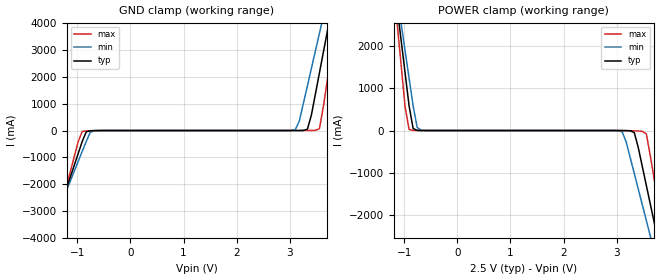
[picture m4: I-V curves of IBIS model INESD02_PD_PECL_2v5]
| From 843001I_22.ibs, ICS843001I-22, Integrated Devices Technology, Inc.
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[Model] INESD02_PD_PECL_2v5
Model_type   Input
Polarity   Non-Inverting
Vinl = 0.8V
Vinh = 2.0V
|   typ   min   max
C_comp   2pF   1.5pF   2.5pF
|   typ   min   max
[Voltage range]  2.5V   2.375V   2.625V
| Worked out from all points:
|   GND clamp passes 1 mA (typ) near -0.59 V on its own axis
|   POWER clamp passes 1 mA (typ) near -0.69 V on its own axis
[GND_clamp]
|Voltage   I(typ)   I(min)   I(max)
-2.5V     -9.799A    -8.591A    -11.84A
-1.591V   -4.431A    -4.121A    -4.98A
-1.439V   -3.536A    -3.377A    -3.837A
-909.1mV  -407.1mA   -774.3mA   -35.24mA
-833.3mV  -48.47mA   -403.4mA   -14.47mA
-681.8mV  -2.863mA   -7.067mA   -5.73mA
3.106V    167.2uA    32.81mA    49.66uA
3.333V    47.81mA    1.661A     649.6uA
3.561V    2.15A      3.618A     75.79mA
3.712V    3.718A     4.923A     1.92A
3.864V    5.287A     6.229A     3.927A
5V        17.07A     16.03A     18.99A
[POWER_clamp]
|Voltage   I(typ)   I(min)   I(max)
-2.5V     17.07A     14.96A     20.65A
-1.136V   2.934A     3.193A     2.572A
-1.061V   2.15A      2.541A     1.569A
-909.1mV  582.4mA    1.237A     24.21mA
-833.3mV  47.81mA    585.7mA    3.595mA
-681.8mV  586.4uA    6.896mA    416.8uA
3.106V    -1.127mA   -30.71mA   -286.5uA
3.333V    -48.47mA   -1.016A    -7.036mA
3.485V    -853.6mA   -1.759A    -17.14mA
3.712V    -2.194A    -2.874A    -1.179A
3.939V    -3.536A    -3.991A    -2.894A
5V        -9.799A    -9.206A    -10.89A
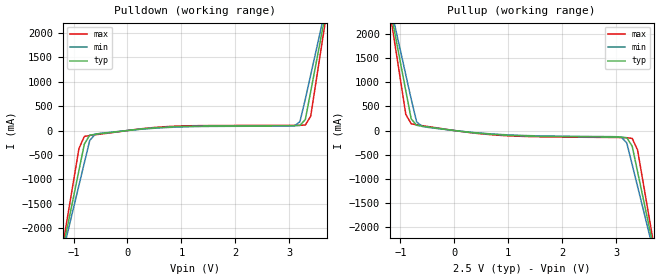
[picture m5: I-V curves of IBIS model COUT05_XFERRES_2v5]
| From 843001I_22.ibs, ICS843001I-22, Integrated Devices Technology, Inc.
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[Model] COUT05_XFERRES_2v5
Model_type   Output
Polarity   Non-Inverting
|   typ   min   max
C_comp   2pF   1.5pF   2.5pF
Vmeas = 1.25V
Rref = 50
Vref = 1.25V
|   typ   min   max
[Voltage range]   2.5V   2.375V   2.625V
[Pullup Reference]   2.5V   2.375V   2.625V
[Pulldown Reference]   0.0V   0.0V   0.0V
[GND Clamp Reference]   0.0V   0.0V   0.0V
[POWER Clamp Reference]   2.5V   2.375V   2.625V
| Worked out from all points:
|   slope of the pulldown table from 0 to 0.375 V, typ, clamps not added: 8.86 ohm
|   slope of the pullup table from 0 to 0.375 V, typ, clamps not added: 7.92 ohm
[pulldown]
|Voltage   I (typ)   I (min)   I (max)
-2.5V     -9.407A    -8.467A    -10.89A
-1.2V     -2.429A    -2.497A    -2.347A
-1.1V     -1.891A    -2.038A    -1.688A
-900mV    -815.3mA   -1.118A    -369.3mA
-800mV    -277.7mA   -658.8mA   -121mA
-600mV    -75.94mA   -74.93mA   -86.3mA
3.1V      97.86mA    96.58mA    105.9mA
3.3V      225.3mA    641.2mA    111.8mA
3.4V      794.9mA    1.136A     294.5mA
3.6V      1.955A     2.127A     1.718A
3.7V      2.536A     2.623A     2.431A
5V        10.13A     9.107A     11.75A
[pullup]
|Voltage   I (typ)   I (min)   I (max)
-2.5V     10.24A     9.216A     11.88A
-1.2V     2.591A     2.667A     2.502A
-1.1V     2.002A     2.164A     1.78A
-900mV    823.6mA    1.156A     334.8mA
-800mV    243.2mA    652.3mA    139.1mA
-600mV    90.17mA    86.22mA    102.1mA
3.1V      -138.3mA   -138.9mA   -146.3mA
3.3V      -324.7mA   -709.4mA   -163.3mA
3.4V      -856.2mA   -1.163A    -404.9mA
3.6V      -1.922A    -2.073A    -1.713A
3.7V      -2.455A    -2.529A    -2.368A
5V        -9.405A    -8.469A    -10.89A
[Ramp]
|   typ   min   max
dV/dt_r   1.50/0.6n   1.50/0.80n   1.50/0.4n
dV/dt_f   1.50/0.6n   1.50/0.80n   1.50/0.4n
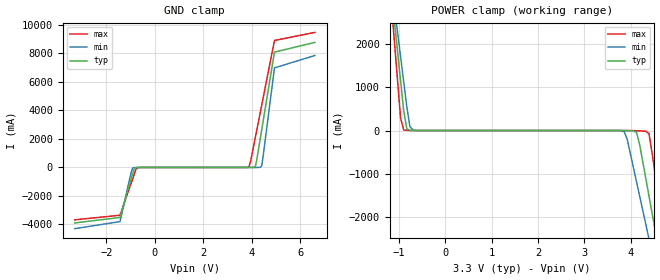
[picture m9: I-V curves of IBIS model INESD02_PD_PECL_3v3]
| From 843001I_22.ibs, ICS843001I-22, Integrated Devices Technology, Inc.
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[Model] INESD02_PD_PECL_3v3
Model_type  Input
Polarity   Non-Inverting
Vinl = 0.8V
Vinh = 2.0V
|   typ   min   max
C_comp   2pF   1.5pF   2.5pF
|   typ   min   max
[Voltage range]  3.3V   3.15V   3.45V
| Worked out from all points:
|   GND clamp passes 1 mA (typ) near -0.59 V on its own axis
|   POWER clamp passes 1 mA (typ) near -0.70 V on its own axis
[GND_clamp]
-3.3V     -3.894A    -4.294A    -3.674A
-1.434V   -3.506A    -3.799A    -3.352A
-974.8mV  -794.1mA   -331.5mA   -1.096A
-909.1mV  -407.1mA   -35.25mA   -774.3mA
-777.8mV  -10.55mA   -10.84mA   -133.1mA
-646.5mV  -1.912mA   -4.151mA   -2.665mA
3.884V    141.8uA    72.03uA    57.99mA
3.95V     342.2uA    75.94uA    423.8mA
4.146V    78.32mA    440.9uA    2.118A
4.409V    2.651A     112.4mA    4.38A
4.934V    8.093A     6.984A     8.908A
6.6V      8.773A     7.854A     9.475A
[POWER_clamp]
-3.3V     6.7A       6.327A     7.39A
-1.165V   3.23A      3.44A      2.951A
-1.031V   1.843A     2.286A     1.176A
-963.9mV  1.149A     1.709A     289.6mA
-896.9mV  456.5mA    1.133A     15.4mA
-695.9mV  792.2uA    10.73mA    555.6uA
3.861V    -556.7uA   -26.14mA   -39.45uA
4.129V    -41.85mA   -1.19A     -4.904mA
4.33V     -1.119A    -2.176A    -17.86mA
4.531V    -2.305A    -3.163A    -1.019A
4.732V    -3.492A    -4.151A    -2.536A
6.6V      -5.075A    -5.468A    -4.558A
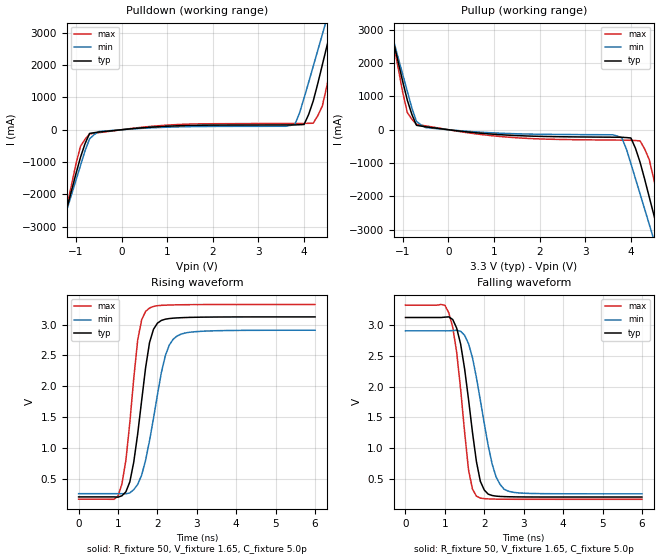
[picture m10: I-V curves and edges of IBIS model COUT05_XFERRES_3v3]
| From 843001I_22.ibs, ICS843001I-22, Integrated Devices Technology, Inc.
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[Model] COUT05_XFERRES_3v3
Model_type   Output
Polarity   Non-Inverting
|   typ   min   max
C_comp   2pF   1.5pF   2.5pF
Vmeas = 1.65V
Rref = 50
Vref = 1.65V
|   typ   min   max
[Voltage range]   3.3V   3.135V   3.465V
[Pullup Reference]   3.3V   3.135V   3.465V
[Pulldown Reference]   0.0V   0.0V   0.0V
[GND Clamp Reference]   0.0V   0.0V   0.0V
[POWER Clamp Reference]   3.3V   3.135V   3.465V
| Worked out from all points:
|   slope of the pulldown table from 0 to 0.495 V, typ, clamps not added: 7.71 ohm
|   slope of the pullup table from 0 to 0.495 V, typ, clamps not added: 6.44 ohm
|   rising waveform, R_fixture 50, V_fixture 1.65, C_fixture 5.0p: 20-80 % time 355ps typ, 463ps min, 291ps max; typ from 0.201 V to 3.12 V
|   falling waveform, R_fixture 50, V_fixture 1.65, C_fixture 5.0p: 20-80 % time 361ps typ, 456ps min, 309ps max; typ from 3.12 V to 0.201 V
[pulldown]
|Voltage   I (typ)   I (min)   I (max)
-3.3V     -13.74A    -12.12A    -16.25A
-1.4V     -3.526A    -3.407A    -3.72A
-1.3V     -2.987A    -2.948A    -3.058A
-900mV    -857.7mA   -1.112A    -513.9mA
-700mV    -114.2mA   -281.1mA   -130.4mA
3.8V      149.8mA    170.1mA    194.9mA
4V        161.9mA    982.2mA    196.3mA
4.2V      887.5mA    1.963A     202.2mA
4.4V      2.009A     2.952A     734.1mA
4.6V      3.172A     3.944A     2.074A
4.8V      4.339A     4.937A     3.509A
6.6V      15.05A     14.04A     16.69A
[pullup]
|Voltage   I (typ)   I (min)   I (max)
-3.3V     15.02A     13.23A     17.78A
-1.3V     3.212A     3.164A     3.296A
-900mV    885.7mA    1.151A     514.2mA
-700mV    133mA      248.7mA    161.5mA
3.6V      -223.7mA   -151.5mA   -310mA
3.8V      -226.2mA   -242.1mA   -312.1mA
4V        -247.6mA   -1.022A    -317.2mA
4.3V      -1.48A     -2.38A     -576.5mA
4.5V      -2.547A    -3.289A    -1.474A
4.6V      -3.081A    -3.743A    -2.13A
4.8V      -4.149A    -4.654A    -3.444A
6.6V      -13.78A    -12.87A    -15.26A
[Ramp]
|   typ   min   max
dV/dt_r   1.98/0.6n   1.98/0.80n   1.98/0.4n
dV/dt_f   1.98/0.6n   1.98/0.80n   1.98/0.4n
[Rising Waveform]
R_fixture = 50
V_fixture = 1.65
V_fixture_max = 1.73
V_fixture_min = 1.57
C_fixture = 5.0p
| Time   typ   min   max
0s        201.4mV    254.1mV    164.2mV
1ns       197.4mV    254.2mV    216.1mV
1.2ns     283.8mV    252.5mV    796.1mV
1.3ns     446.3mV    266.1mV    1.409V
1.5ns     1.228V     405mV      2.752V
1.6ns     1.766V     555.2mV    3.078V
1.8ns     2.708V     1.114V     3.269V
2.2ns     3.087V     2.492V     3.315V
2.5ns     3.108V     2.815V     3.321V
6ns       3.125V     2.908V     3.326V
[Falling Waveform]
R_fixture = 50
V_fixture = 1.65
V_fixture_max = 1.73
V_fixture_min = 1.57
C_fixture = 5.0p
| Time   typ   min   max
0s        3.125V     2.908V     3.326V
1.1ns     3.135V     2.908V     3.198V
1.3ns     2.95V      2.917V     2.555V
1.4ns     2.69V      2.901V     1.954V
1.6ns     1.791V     2.699V     643mV
1.8ns     779.8mV    2.147V     216.4mV
2ns       315.1mV    1.396V     175.1mV
2.2ns     226.3mV    737.5mV    169mV
2.5ns     208.7mV    330.3mV    166.1mV
6ns       201.4mV    254.1mV    164.2mV
